# Generated by FakeRAM 2.0
VERSION 5.7 ;
BUSBITCHARS "[]" ;
PROPERTYDEFINITIONS
  MACRO width INTEGER ;
  MACRO depth INTEGER ;
  MACRO banks INTEGER ;
END PROPERTYDEFINITIONS
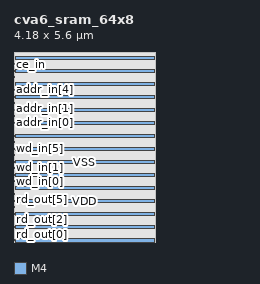
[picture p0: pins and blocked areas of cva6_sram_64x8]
MACRO cva6_sram_64x8
  PROPERTY width 8 ;
  PROPERTY depth 64 ;
  PROPERTY banks 1 ;
  FOREIGN cva6_sram_64x8 0 0 ;
  SYMMETRY X Y R90 ;
  SIZE 4.1800 BY 5.6000 ;
  CLASS BLOCK ;
  PIN rd_out[0]
    DIRECTION OUTPUT ;
    USE SIGNAL ;
    PORT
      LAYER M4 ;
      RECT 0.00000 0.04800 0.02400 0.07200 ;
    END
  END rd_out[0]
  PIN rd_out[1]
    DIRECTION OUTPUT ;
    USE SIGNAL ;
    PORT
      LAYER M4 ;
      RECT 0.00000 0.24000 0.02400 0.26400 ;
    END
  END rd_out[1]
  PIN rd_out[2]
    DIRECTION OUTPUT ;
    USE SIGNAL ;
    PORT
      LAYER M4 ;
      RECT 0.00000 0.43200 0.02400 0.45600 ;
    END
  END rd_out[2]
  PIN rd_out[3]
    DIRECTION OUTPUT ;
    USE SIGNAL ;
    PORT
      LAYER M4 ;
      RECT 0.00000 0.62400 0.02400 0.64800 ;
    END
  END rd_out[3]
  PIN rd_out[4]
    DIRECTION OUTPUT ;
    USE SIGNAL ;
    PORT
      LAYER M4 ;
      RECT 0.00000 0.81600 0.02400 0.84000 ;
    END
  END rd_out[4]
  PIN rd_out[5]
    DIRECTION OUTPUT ;
    USE SIGNAL ;
    PORT
      LAYER M4 ;
      RECT 0.00000 1.00800 0.02400 1.03200 ;
    END
  END rd_out[5]
  PIN rd_out[6]
    DIRECTION OUTPUT ;
    USE SIGNAL ;
    PORT
      LAYER M4 ;
      RECT 0.00000 1.20000 0.02400 1.22400 ;
    END
  END rd_out[6]
  PIN rd_out[7]
    DIRECTION OUTPUT ;
    USE SIGNAL ;
    PORT
      LAYER M4 ;
      RECT 0.00000 1.39200 0.02400 1.41600 ;
    END
  END rd_out[7]
  PIN wd_in[0]
    DIRECTION INPUT ;
    USE SIGNAL ;
    PORT
      LAYER M4 ;
      RECT 0.00000 1.77600 0.02400 1.80000 ;
    END
  END wd_in[0]
  PIN wd_in[1]
    DIRECTION INPUT ;
    USE SIGNAL ;
    PORT
      LAYER M4 ;
      RECT 0.00000 1.96800 0.02400 1.99200 ;
    END
  END wd_in[1]
  PIN wd_in[2]
    DIRECTION INPUT ;
    USE SIGNAL ;
    PORT
      LAYER M4 ;
      RECT 0.00000 2.16000 0.02400 2.18400 ;
    END
  END wd_in[2]
  PIN wd_in[3]
    DIRECTION INPUT ;
    USE SIGNAL ;
    PORT
      LAYER M4 ;
      RECT 0.00000 2.35200 0.02400 2.37600 ;
    END
  END wd_in[3]
  PIN wd_in[4]
    DIRECTION INPUT ;
    USE SIGNAL ;
    PORT
      LAYER M4 ;
      RECT 0.00000 2.54400 0.02400 2.56800 ;
    END
  END wd_in[4]
  PIN wd_in[5]
    DIRECTION INPUT ;
    USE SIGNAL ;
    PORT
      LAYER M4 ;
      RECT 0.00000 2.73600 0.02400 2.76000 ;
    END
  END wd_in[5]
  PIN wd_in[6]
    DIRECTION INPUT ;
    USE SIGNAL ;
    PORT
      LAYER M4 ;
      RECT 0.00000 2.92800 0.02400 2.95200 ;
    END
  END wd_in[6]
  PIN wd_in[7]
    DIRECTION INPUT ;
    USE SIGNAL ;
    PORT
      LAYER M4 ;
      RECT 0.00000 3.12000 0.02400 3.14400 ;
    END
  END wd_in[7]
  PIN addr_in[0]
    DIRECTION INPUT ;
    USE SIGNAL ;
    PORT
      LAYER M4 ;
      RECT 0.00000 3.50400 0.02400 3.52800 ;
    END
  END addr_in[0]
  PIN addr_in[1]
    DIRECTION INPUT ;
    USE SIGNAL ;
    PORT
      LAYER M4 ;
      RECT 0.00000 3.69600 0.02400 3.72000 ;
    END
  END addr_in[1]
  PIN addr_in[2]
    DIRECTION INPUT ;
    USE SIGNAL ;
    PORT
      LAYER M4 ;
      RECT 0.00000 3.88800 0.02400 3.91200 ;
    END
  END addr_in[2]
  PIN addr_in[3]
    DIRECTION INPUT ;
    USE SIGNAL ;
    PORT
      LAYER M4 ;
      RECT 0.00000 4.08000 0.02400 4.10400 ;
    END
  END addr_in[3]
  PIN addr_in[4]
    DIRECTION INPUT ;
    USE SIGNAL ;
    PORT
      LAYER M4 ;
      RECT 0.00000 4.27200 0.02400 4.29600 ;
    END
  END addr_in[4]
  PIN addr_in[5]
    DIRECTION INPUT ;
    USE SIGNAL ;
    PORT
      LAYER M4 ;
      RECT 0.00000 4.46400 0.02400 4.48800 ;
    END
  END addr_in[5]
  PIN we_in
    DIRECTION INPUT ;
    USE SIGNAL ;
    PORT
      LAYER M4 ;
      RECT 0.00000 4.84800 0.02400 4.87200 ;
    END
  END we_in
  PIN clk
    DIRECTION INPUT ;
    USE SIGNAL ;
    PORT
      LAYER M4 ;
      RECT 0.00000 5.04000 0.02400 5.06400 ;
    END
  END clk
  PIN ce_in
    DIRECTION INPUT ;
    USE SIGNAL ;
    PORT
      LAYER M4 ;
      RECT 0.00000 5.23200 0.02400 5.25600 ;
    END
  END ce_in
  PIN VDD
    DIRECTION INOUT ;
    USE POWER ;
    PORT
      LAYER M4 ;
      RECT 0.04800 0.38400 4.13200 0.48000 ;
      RECT 0.04800 1.15200 4.13200 1.24800 ;
      RECT 0.04800 1.92000 4.13200 2.01600 ;
      RECT 0.04800 2.68800 4.13200 2.78400 ;
      RECT 0.04800 3.45600 4.13200 3.55200 ;
      RECT 0.04800 4.22400 4.13200 4.32000 ;
      RECT 0.04800 4.99200 4.13200 5.08800 ;
    END
  END VDD
  PIN VSS
    DIRECTION INOUT ;
    USE GROUND ;
    PORT
      LAYER M4 ;
      RECT 0.04800 0.00000 4.13200 0.09600 ;
      RECT 0.04800 0.76800 4.13200 0.86400 ;
      RECT 0.04800 1.53600 4.13200 1.63200 ;
      RECT 0.04800 2.30400 4.13200 2.40000 ;
      RECT 0.04800 3.07200 4.13200 3.16800 ;
      RECT 0.04800 3.84000 4.13200 3.93600 ;
      RECT 0.04800 4.60800 4.13200 4.70400 ;
      RECT 0.04800 5.37600 4.13200 5.47200 ;
    END
  END VSS
  OBS
    LAYER M1 ;
    RECT 0 0 4.18000 5.60000 ;
    LAYER M2 ;
    RECT 0 0 4.18000 5.60000 ;
    LAYER M3 ;
    RECT 0 0 4.18000 5.60000 ;
    LAYER M4 ;
    RECT 0 0 4.18000 5.60000 ;
  END
END cva6_sram_64x8

END LIBRARY
